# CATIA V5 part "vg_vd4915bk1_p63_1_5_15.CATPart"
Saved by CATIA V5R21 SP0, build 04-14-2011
Part number: vg_vd4915bk1_p63_1_5_15
Bounding box of the stored display mesh (mm): x 0 to 50.7, y -31.5 to 31.5, z -31.5 to 31.5
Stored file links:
  C:\TPO v2\SharedFS\Outgoing\vg_vd4915bk1_p63_1_5_15.CATPart

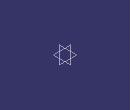
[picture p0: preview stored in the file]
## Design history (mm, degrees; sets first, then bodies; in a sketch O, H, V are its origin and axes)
AxisSystem1: origin (0, 0, 0), X (1, 0, 0), Y (0, 1, 0), Z (0, 0, 1)
Body1 "vg_vd4915bk1_p63_1_5_15" (main body)
  Solid1: solid without history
